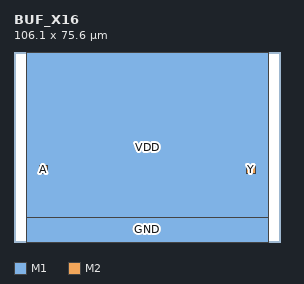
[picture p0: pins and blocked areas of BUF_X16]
MACRO BUF_X16
  CLASS CORE ;
  ORIGIN 0 0 ;
  SIZE 106.100 BY 75.600 ;
  SYMMETRY X Y ;
  SITE TR1um_access_site ;
  PIN VDD
    DIRECTION INOUT ;
    USE POWER ;
    PORT
      LAYER M1 ;
        RECT 5.000 0.000 101.100 75.600 ;
    END
  END VDD
  PIN GND
    DIRECTION INOUT ;
    USE GROUND ;
    PORT
      LAYER M1 ;
        RECT 5.000 0.000 101.100 9.800 ;
    END
  END GND
  PIN A
    DIRECTION INPUT ;
    USE SIGNAL ;
    PORT
      LAYER M2 ;
        RECT 10.100 27.100 13.500 30.500 ;
    END
  END A
  PIN Y
    DIRECTION OUTPUT ;
    USE SIGNAL ;
    PORT
      LAYER M2 ;
        RECT 92.600 27.100 96.000 30.500 ;
    END
  END Y
  OBS
    LAYER M1 ;
      RECT 33.100 6.400 52.150 14.000 ;
    LAYER M1 ;
      RECT 36.600 15.900 52.150 18.500 ;
    LAYER M1 ;
      RECT 10.100 22.000 14.500 30.500 ;
    LAYER M1 ;
      RECT 36.600 32.300 52.150 34.900 ;
    LAYER M1 ;
      RECT 53.950 15.900 87.700 34.900 ;
    LAYER M1 ;
      RECT 13.100 6.400 52.150 51.200 ;
    LAYER M1 ;
      RECT 33.100 36.800 52.150 51.200 ;
    LAYER M1 ;
      RECT 53.950 6.400 96.000 51.200 ;
    LAYER V1 ;
      RECT 11.100 28.100 12.500 29.500 ;
    LAYER V1 ;
      RECT 93.600 28.100 95.000 29.500 ;
  END
END BUF_X16
